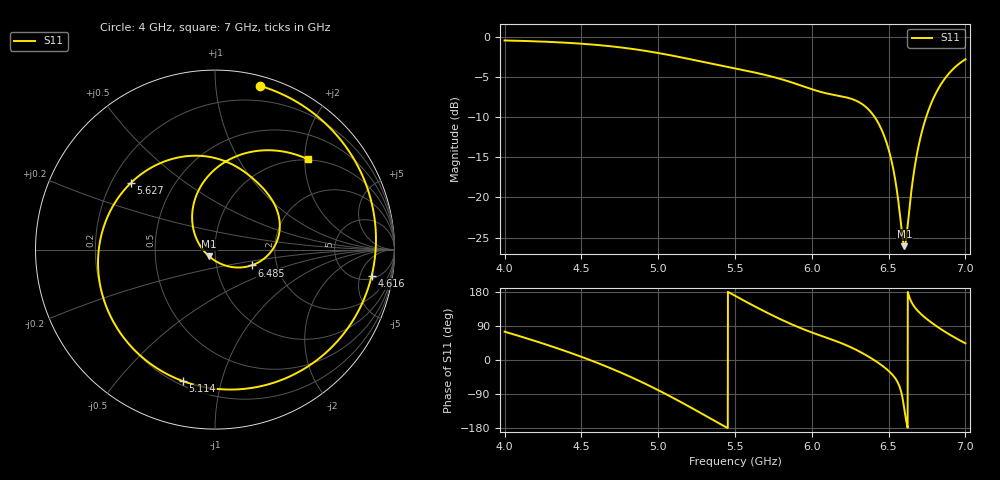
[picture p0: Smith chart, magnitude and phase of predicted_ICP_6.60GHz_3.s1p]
! ICP-predicted S11, target max centred GHz at -10 dB. Complex ensemble mean (passive and causal);
! its |S11| can differ slightly from the dB-domain mean reported in designs.csv.
!  Air_gap = 4.11mm
!  W_Patch = 15.23mm
!  L_Patch = 15.59mm
!  Sx = 1.1mm
!  Sy = 2.78mm
!  W_Patch1 = 8.13mm
!  WS = 0.55mm
!  Curve_Amp1 = 0.67mm
!  Extra = 5.92mm
# GHz S MA R 50
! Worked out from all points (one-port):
!   3001 points, 4 GHz to 7 GHz, reference 50 ohm
!   lowest |S11| = -26.1 dB at 6.603 GHz (marker M1), VSWR 1.10, Z = 46.7 - j3.53 ohm
!   |S11| at or under -10 dB: 6.409 GHz to 6.745 GHz (335.5 MHz wide, 5.1 % of centre)
!   S11 on the Smith chart (normalised r, x): 4 GHz: 0.07, +1.31; 4.616 GHz: 5.76, -7.78; 5.114 GHz: 0.22, -0.76; 5.627 GHz: 0.28, +0.32; 6.485 GHz: 1.48, -0.27; 7 GHz: 0.99, +2.08
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4  0.9465 74.8
4.182  0.9361 52.3
4.375  0.919 26.5
4.5  0.9034 8.5
4.616  0.8849 -9.5
4.75  0.858 -32.0
4.944  0.8076 -68.3
5.114  0.7544 -103.6
5.125  0.7508 -106.0
5.229  0.7167 -129.1
5.32  0.6876 -149.7
5.409  0.6606 -170.0
5.5  0.6343 169.5
5.627  0.5984 141.8
5.748  0.5614 117.0
5.875  0.5169 93.1
6.028  0.4618 68.6
6.25  0.4125 34.4
6.372  0.3502 8.3
6.485  0.2216 -23.4
6.536  0.1408 -44.2
6.589  0.0578 -96.9
6.603  0.04976 -130.9
6.625  0.06826 179.6
6.681  0.1782 133.8
6.755  0.3382 106.1
6.877  0.5655 72.1
7  0.7227 44.0
